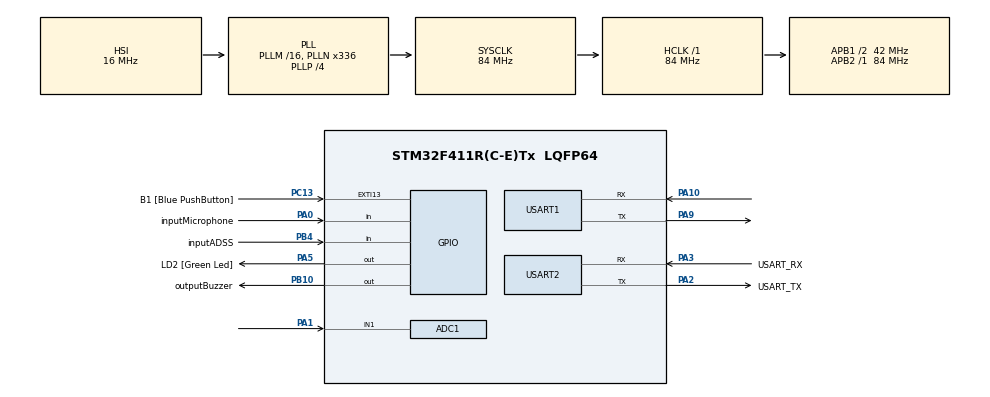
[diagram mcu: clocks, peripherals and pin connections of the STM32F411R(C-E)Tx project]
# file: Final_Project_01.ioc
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ADC1.Channel-0\#ChannelRegularConversion=ADC_CHANNEL_1
ADC1.NbrOfConversionFlag=1
ADC1.Rank-0\#ChannelRegularConversion=1
ADC1.SamplingTime-0\#ChannelRegularConversion=ADC_SAMPLETIME_3CYCLES
ADC1.master=1
Dma.Request0=USART2_RX
Dma.Request1=USART2_TX
Dma.Request2=USART1_RX
Dma.Request3=USART1_TX
Dma.USART1_RX.2.Direction=DMA_PERIPH_TO_MEMORY
Dma.USART1_RX.2.FIFOMode=DMA_FIFOMODE_DISABLE
Dma.USART1_RX.2.Instance=DMA2_Stream2
Dma.USART1_RX.2.MemDataAlignment=DMA_MDATAALIGN_BYTE
Dma.USART1_RX.2.MemInc=DMA_MINC_ENABLE
Dma.USART1_RX.2.Mode=DMA_NORMAL
Dma.USART1_RX.2.PeriphDataAlignment=DMA_PDATAALIGN_BYTE
Dma.USART1_RX.2.PeriphInc=DMA_PINC_DISABLE
Dma.USART1_RX.2.Priority=DMA_PRIORITY_LOW
Dma.USART1_TX.3.Direction=DMA_MEMORY_TO_PERIPH
Dma.USART1_TX.3.FIFOMode=DMA_FIFOMODE_DISABLE
Dma.USART1_TX.3.Instance=DMA2_Stream7
Dma.USART1_TX.3.MemDataAlignment=DMA_MDATAALIGN_BYTE
Dma.USART1_TX.3.MemInc=DMA_MINC_ENABLE
Dma.USART1_TX.3.Mode=DMA_NORMAL
Dma.USART1_TX.3.PeriphDataAlignment=DMA_PDATAALIGN_BYTE
Dma.USART1_TX.3.PeriphInc=DMA_PINC_DISABLE
Dma.USART1_TX.3.Priority=DMA_PRIORITY_LOW
Dma.USART2_RX.0.Direction=DMA_PERIPH_TO_MEMORY
Dma.USART2_RX.0.FIFOMode=DMA_FIFOMODE_DISABLE
Dma.USART2_RX.0.Instance=DMA1_Stream5
Dma.USART2_RX.0.MemDataAlignment=DMA_MDATAALIGN_BYTE
Dma.USART2_RX.0.MemInc=DMA_MINC_ENABLE
Dma.USART2_RX.0.Mode=DMA_NORMAL
Dma.USART2_RX.0.PeriphDataAlignment=DMA_PDATAALIGN_BYTE
Dma.USART2_RX.0.PeriphInc=DMA_PINC_DISABLE
Dma.USART2_RX.0.Priority=DMA_PRIORITY_LOW
Dma.USART2_TX.1.Direction=DMA_MEMORY_TO_PERIPH
Dma.USART2_TX.1.FIFOMode=DMA_FIFOMODE_DISABLE
Dma.USART2_TX.1.Instance=DMA1_Stream6
Dma.USART2_TX.1.MemDataAlignment=DMA_MDATAALIGN_BYTE
Dma.USART2_TX.1.MemInc=DMA_MINC_ENABLE
Dma.USART2_TX.1.Mode=DMA_NORMAL
Dma.USART2_TX.1.PeriphDataAlignment=DMA_PDATAALIGN_BYTE
Dma.USART2_TX.1.PeriphInc=DMA_PINC_DISABLE
Dma.USART2_TX.1.Priority=DMA_PRIORITY_LOW
Mcu.Family=STM32F4
Mcu.Name=STM32F411R(C-E)Tx
Mcu.Package=LQFP64
NVIC.DMA1_Stream5_IRQn=true\:0\:0\:false\:false\:true\:false\:true\:true
NVIC.DMA1_Stream6_IRQn=true\:0\:0\:false\:false\:true\:false\:true\:true
NVIC.DMA2_Stream2_IRQn=true\:0\:0\:false\:false\:true\:false\:true\:true
NVIC.DMA2_Stream7_IRQn=true\:0\:0\:false\:false\:true\:false\:true\:true
NVIC.EXTI15_10_IRQn=true\:0\:0\:false\:false\:true\:true\:true\:true
NVIC.PriorityGroup=NVIC_PRIORITYGROUP_0
NVIC.USART2_IRQn=true\:0\:0\:false\:false\:true\:true\:true\:true
PA0-WKUP.GPIO_Label=inputMicrophone
PA0-WKUP.Signal=GPIO_Input
PA1.Signal=ADCx_IN1
PA10.Mode=Asynchronous
PA10.Signal=USART1_RX
PA13.GPIO_Label=TMS
PA13.Mode=Serial_Wire
PA13.Signal=SYS_JTMS-SWDIO
PA14.GPIO_Label=TCK
PA14.Mode=Serial_Wire
PA14.Signal=SYS_JTCK-SWCLK
PA2.GPIO_Label=USART_TX
PA2.Mode=Asynchronous
PA2.Signal=USART2_TX
PA3.GPIO_Label=USART_RX
PA3.Mode=Asynchronous
PA3.Signal=USART2_RX
PA5.GPIO_Label=LD2 [Green Led]
PA5.Signal=GPIO_Output
PA9.Mode=Asynchronous
PA9.Signal=USART1_TX
PB10.GPIO_Label=outputBuzzer
PB10.Signal=GPIO_Output
PB3.GPIO_Label=SWO
PB3.Signal=SYS_JTDO-SWO
PB4.GPIO_Label=inputADSS
PB4.Signal=GPIO_Input
PC13-ANTI_TAMP.GPIO_Label=B1 [Blue PushButton]
PC13-ANTI_TAMP.GPIO_ModeDefaultEXTI=GPIO_MODE_IT_FALLING
PC13-ANTI_TAMP.Signal=GPXTI13
PC14-OSC32_IN.Mode=LSE-External-Oscillator
PC14-OSC32_IN.Signal=RCC_OSC32_IN
PC15-OSC32_OUT.Mode=LSE-External-Oscillator
PC15-OSC32_OUT.Signal=RCC_OSC32_OUT
PH0\ -\ OSC_IN.Mode=HSE-External-Clock-Source
PH0\ -\ OSC_IN.Signal=RCC_OSC_IN
PH1\ -\ OSC_OUT.Mode=HSE-External-Clock-Source
PH1\ -\ OSC_OUT.Signal=RCC_OSC_OUT
ProjectManager.HeapSize=0x200
ProjectManager.StackSize=0x400
ProjectManager.TargetToolchain=STM32CubeIDE
RCC.48MHZClocksFreq_Value=84000000
RCC.AHBFreq_Value=84000000
RCC.APB1CLKDivider=RCC_HCLK_DIV2
RCC.APB1Freq_Value=42000000
RCC.APB1TimFreq_Value=84000000
RCC.APB2Freq_Value=84000000
RCC.APB2TimFreq_Value=84000000
RCC.CortexFreq_Value=84000000
RCC.FLatency-AdvancedSettings=FLASH_LATENCY_2
RCC.HCLKFreq_Value=84000000
RCC.HSE_VALUE=8000000
RCC.HSI_VALUE=16000000
RCC.PLLN=336
RCC.PLLP=RCC_PLLP_DIV4
RCC.SYSCLKFreq_VALUE=84000000
RCC.SYSCLKSource=RCC_SYSCLKSOURCE_PLLCLK
RCC.VCOOutputFreq_Value=336000000
SH.ADCx_IN1.0=ADC1_IN1,IN1
USART1.VirtualMode=VM_ASYNC
USART2.VirtualMode=VM_ASYNC
board=NUCLEO-F411RE

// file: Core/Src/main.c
/* USER CODE BEGIN Header */
/**
 ******************************************************************************
 * @file           : main.c
 * @brief          : Main program body
 ******************************************************************************
 * @attention
 *
 * Copyright (c) 2025 STMicroelectronics.
 * All rights reserved.
 *
 * This software is licensed under terms that can be found in the LICENSE file
 * in the root directory of this software component.
 * If no LICENSE file comes with this software, it is provided AS-IS.
 *
 ******************************************************************************
 */
/* USER CODE END Header */
#include "main.h"

ADC_HandleTypeDef hadc1;

UART_HandleTypeDef huart1;
UART_HandleTypeDef huart2;

/* USER CODE BEGIN PV */
volatile uint32_t last_object_seen_time = 0;  // เวลาล่าสุดที่เจอวัตถุ (IR)
volatile uint32_t last_noise_seen_time = 0;  // เวลาล่าสุดที่เจอเสียง (จาก A0)
int previous_alarm_state = 0;
/* USER CODE END PV */

void SystemClock_Config(void);
static void MX_GPIO_Init(void);
static void MX_USART2_UART_Init(void);
static void MX_ADC1_Init(void);
static void MX_USART1_UART_Init(void);
/* USER CODE BEGIN PFP */
void SendAlarmStatus(const char *status);
/* USER CODE END PFP */

int main(void) {

	/* MCU Configuration--------------------------------------------------------*/

	/* Reset of all peripherals, Initializes the Flash interface and the Systick. */
	HAL_Init();

	/* Configure the system clock */
	SystemClock_Config();

	/* Initialize all configured peripherals */
	MX_GPIO_Init();
	MX_USART2_UART_Init();
	MX_ADC1_Init();
	MX_USART1_UART_Init();

	/* Infinite loop */
	while (1) {
		/* -------- 1) อ่านสถานะจาก IR Sensor (Infrared_Pin, Active Low) -------- */
		GPIO_PinState ir_state = HAL_GPIO_ReadPin(Infrared_GPIO_Port,
		Infrared_Pin);
		if (ir_state == GPIO_PIN_RESET) {
			last_object_seen_time = HAL_GetTick();
		}
		// ถ้า 200ms ล่าสุดยังเคยเจอวัตถุอยู่ -> is_obstacle = 1
		uint8_t is_obstacle = (HAL_GetTick() - last_object_seen_time) < 200;

		/* -------- 2) อ่านเสียงจาก A0 (ADC1_CH1 = PA1) -------- */
		uint32_t min_val = 4095;
		uint32_t max_val = 0;
		uint64_t sum_val = 0;
		const int N = 500;  // จำนวน sample ต่อรอบ

		for (int i = 0; i < N; i++) {
			HAL_ADC_Start(&hadc1);
			HAL_ADC_PollForConversion(&hadc1, HAL_MAX_DELAY);
			uint32_t v = HAL_ADC_GetValue(&hadc1);
			HAL_ADC_Stop(&hadc1);

			if (v < min_val)
				min_val = v;
			if (v > max_val)
				max_val = v;
			sum_val += v;
		}

		uint32_t avg_val = (uint32_t) (sum_val / N);
		uint32_t range_val = max_val - min_val;

		// ถ้า range ของสัญญาณเสียงเกิน threshold -> ถือว่าเจอเสียงดัง
		// (ค่า 1000 เป็นค่าลองเบื้องต้น ปรับเพิ่ม/ลดได้ตามของจริง)
		if (range_val > 1000) {
			last_noise_seen_time = HAL_GetTick();
		}

		// 2 วินาทีล่าสุดถ้ายังเจอเสียงดัง -> is_noise = 1
		uint8_t is_noise = (HAL_GetTick() - last_noise_seen_time) < 2000;

		/* -------- (Debug optional) แสดงค่าเสียงบางครั้ง -------- */
		static uint32_t last_print = 0;
		if (HAL_GetTick() - last_print > 100) {
			char buf[80];
			snprintf(buf, sizeof(buf),
					"Sound: range=%lu avg=%lu (thr=1000)\r\n",
					(unsigned long) range_val, (unsigned long) avg_val);
			HAL_UART_Transmit(&huart2, (uint8_t*) buf, strlen(buf), 50);
			last_print = HAL_GetTick();
		}

		/* -------- 3) รวมเป็นสถานะ Alarm -------- */
		uint8_t current_alarm_state = (is_obstacle || is_noise);

		/* -------- 4) ถ้าสถานะ Alarm เปลี่ยน -> รายงาน + คุม LED/Buzzer -------- */
		if (current_alarm_state != previous_alarm_state) {
			char msg[100];

			if (current_alarm_state == 1) {
				// Alarm ON
				sprintf(msg, "ALARM! State: %s%s\r\n",
						is_obstacle ? "OBSTACLE " : "",
						is_noise ? "NOISE" : "");

				// เปิด LED
				HAL_GPIO_WritePin(LED_GPIO_Port, LED_Pin, GPIO_PIN_SET);

				// ส่งสถานะไป ESP32
				if (is_obstacle && is_noise) {
					SendAlarmStatus("ALARM_BOTH\r\n");
				} else if (is_obstacle) {
					SendAlarmStatus("ALARM_OBSTACLE\r\n");
				} else if (is_noise) {
					SendAlarmStatus("ALARM_NOISE\r\n");
				}

			} else {
				// Alarm OFF
				sprintf(msg, "CLEARED! System Idle.\r\n");

				// ปิด LED
				HAL_GPIO_WritePin(LED_GPIO_Port, LED_Pin, GPIO_PIN_RESET);

				// ปิด Buzzer ทันที
				HAL_GPIO_WritePin(Buzzer_GPIO_Port, Buzzer_Pin, GPIO_PIN_RESET);

				// ส่งสถานะไป ESP32
				SendAlarmStatus("ALARM_CLEARED\r\n");
			}

			HAL_UART_Transmit(&huart2, (uint8_t*) msg, strlen(msg),
			HAL_MAX_DELAY);
			previous_alarm_state = current_alarm_state;
		}

		/* -------- 5) สร้างเสียง Buzzer ขณะ Alarm ON -------- */
		if (current_alarm_state == 1) {
			// Toggle Buzzer ให้เกิดโทนเสียง (ความถี่ประมาณ 500Hz ถ้าหน่วง 1ms)
			HAL_GPIO_TogglePin(Buzzer_GPIO_Port, Buzzer_Pin);
			HAL_Delay(1);
		} else {
			HAL_Delay(10); // Idle เบา ๆ ตอนไม่มี Alarm
		}
	}
}

void SystemClock_Config(void) {
	RCC_OscInitTypeDef RCC_OscInitStruct = { 0 };
	RCC_ClkInitTypeDef RCC_ClkInitStruct = { 0 };

	/** Configure the main internal regulator output voltage
	 */
	__HAL_RCC_PWR_CLK_ENABLE();
	__HAL_PWR_VOLTAGESCALING_CONFIG(PWR_REGULATOR_VOLTAGE_SCALE1);

	/** Initializes the RCC Oscillators according to the specified parameters
	 * in the RCC_OscInitTypeDef structure.
	 */
	RCC_OscInitStruct.OscillatorType = RCC_OSCILLATORTYPE_HSI;
	RCC_OscInitStruct.HSIState = RCC_HSI_ON;
	RCC_OscInitStruct.HSICalibrationValue = RCC_HSICALIBRATION_DEFAULT;
	RCC_OscInitStruct.PLL.PLLState = RCC_PLL_ON;
	RCC_OscInitStruct.PLL.PLLSource = RCC_PLLSOURCE_HSI;
	RCC_OscInitStruct.PLL.PLLM = 16;
	RCC_OscInitStruct.PLL.PLLN = 336;
	RCC_OscInitStruct.PLL.PLLP = RCC_PLLP_DIV4;
	RCC_OscInitStruct.PLL.PLLQ = 4;
	if (HAL_RCC_OscConfig(&RCC_OscInitStruct) != HAL_OK) {
		Error_Handler();
	}

	/** Initializes the CPU, AHB and APB buses clocks
	 */
	RCC_ClkInitStruct.ClockType = RCC_CLOCKTYPE_HCLK | RCC_CLOCKTYPE_SYSCLK
			| RCC_CLOCKTYPE_PCLK1 | RCC_CLOCKTYPE_PCLK2;
	RCC_ClkInitStruct.SYSCLKSource = RCC_SYSCLKSOURCE_PLLCLK;
	RCC_ClkInitStruct.AHBCLKDivider = RCC_SYSCLK_DIV1;
	RCC_ClkInitStruct.APB1CLKDivider = RCC_HCLK_DIV2;
	RCC_ClkInitStruct.APB2CLKDivider = RCC_HCLK_DIV1;

	if (HAL_RCC_ClockConfig(&RCC_ClkInitStruct, FLASH_LATENCY_2) != HAL_OK) {
		Error_Handler();
	}
}

static void MX_ADC1_Init(void) {

	ADC_ChannelConfTypeDef sConfig = { 0 };

	/** Configure the global features of the ADC (Clock, Resolution, Data Alignment and number of conversion)
	 */
	hadc1.Instance = ADC1;
	hadc1.Init.ClockPrescaler = ADC_CLOCK_SYNC_PCLK_DIV4;
	hadc1.Init.Resolution = ADC_RESOLUTION_12B;
	hadc1.Init.ScanConvMode = DISABLE;
	hadc1.Init.ContinuousConvMode = DISABLE;
	hadc1.Init.DiscontinuousConvMode = DISABLE;
	hadc1.Init.ExternalTrigConvEdge = ADC_EXTERNALTRIGCONVEDGE_NONE;
	hadc1.Init.ExternalTrigConv = ADC_SOFTWARE_START;
	hadc1.Init.DataAlign = ADC_DATAALIGN_RIGHT;
	hadc1.Init.NbrOfConversion = 1;
	hadc1.Init.DMAContinuousRequests = DISABLE;
	hadc1.Init.EOCSelection = ADC_EOC_SINGLE_CONV;
	if (HAL_ADC_Init(&hadc1) != HAL_OK) {
		Error_Handler();
	}

	/** Configure for the selected ADC regular channel its corresponding rank in the sequencer and its sample time.
	 */
	sConfig.Channel = ADC_CHANNEL_1;
	sConfig.Rank = 1;
	sConfig.SamplingTime = ADC_SAMPLETIME_3CYCLES;
	if (HAL_ADC_ConfigChannel(&hadc1, &sConfig) != HAL_OK) {
		Error_Handler();
	}

}

static void MX_USART1_UART_Init(void) {

	huart1.Instance = USART1;
	huart1.Init.BaudRate = 115200;
	huart1.Init.WordLength = UART_WORDLENGTH_8B;
	huart1.Init.StopBits = UART_STOPBITS_1;
	huart1.Init.Parity = UART_PARITY_NONE;
	huart1.Init.Mode = UART_MODE_TX_RX;
	huart1.Init.HwFlowCtl = UART_HWCONTROL_NONE;
	huart1.Init.OverSampling = UART_OVERSAMPLING_16;
	if (HAL_UART_Init(&huart1) != HAL_OK) {
		Error_Handler();
	}

}

static void MX_USART2_UART_Init(void) {

	huart2.Instance = USART2;
	huart2.Init.BaudRate = 115200;
	huart2.Init.WordLength = UART_WORDLENGTH_8B;
	huart2.Init.StopBits = UART_STOPBITS_1;
	huart2.Init.Parity = UART_PARITY_NONE;
	huart2.Init.Mode = UART_MODE_TX_RX;
	huart2.Init.HwFlowCtl = UART_HWCONTROL_NONE;
	huart2.Init.OverSampling = UART_OVERSAMPLING_16;
	if (HAL_UART_Init(&huart2) != HAL_OK) {
		Error_Handler();
	}

}

static void MX_GPIO_Init(void) {
	GPIO_InitTypeDef GPIO_InitStruct = { 0 };

	/* GPIO Ports Clock Enable */
	__HAL_RCC_GPIOC_CLK_ENABLE();
	__HAL_RCC_GPIOH_CLK_ENABLE();
	__HAL_RCC_GPIOA_CLK_ENABLE();
	__HAL_RCC_GPIOB_CLK_ENABLE();

	/*Configure GPIO pin Output Level */
	HAL_GPIO_WritePin(LED_GPIO_Port, LED_Pin, GPIO_PIN_RESET);

	/*Configure GPIO pin Output Level */
	HAL_GPIO_WritePin(Buzzer_GPIO_Port, Buzzer_Pin, GPIO_PIN_RESET);

	/*Configure GPIO pin : B1_Pin */
	GPIO_InitStruct.Pin = B1_Pin;
	GPIO_InitStruct.Mode = GPIO_MODE_IT_FALLING;
	GPIO_InitStruct.Pull = GPIO_NOPULL;
	HAL_GPIO_Init(B1_GPIO_Port, &GPIO_InitStruct);

	/*Configure GPIO pin : SOUND_IN_Pin */
	GPIO_InitStruct.Pin = SOUND_IN_Pin;
	GPIO_InitStruct.Mode = GPIO_MODE_INPUT;
	GPIO_InitStruct.Pull = GPIO_PULLDOWN;
	HAL_GPIO_Init(SOUND_IN_GPIO_Port, &GPIO_InitStruct);

	/*Configure GPIO pin : LED_Pin */
	GPIO_InitStruct.Pin = LED_Pin;
	GPIO_InitStruct.Mode = GPIO_MODE_OUTPUT_PP;
	GPIO_InitStruct.Pull = GPIO_NOPULL;
	GPIO_InitStruct.Speed = GPIO_SPEED_FREQ_LOW;
	HAL_GPIO_Init(LED_GPIO_Port, &GPIO_InitStruct);

	/*Configure GPIO pin : Buzzer_Pin */
	GPIO_InitStruct.Pin = Buzzer_Pin;
	GPIO_InitStruct.Mode = GPIO_MODE_OUTPUT_PP;
	GPIO_InitStruct.Pull = GPIO_NOPULL;
	GPIO_InitStruct.Speed = GPIO_SPEED_FREQ_LOW;
	HAL_GPIO_Init(Buzzer_GPIO_Port, &GPIO_InitStruct);

	/*Configure GPIO pin : Infrared_Pin */
	GPIO_InitStruct.Pin = Infrared_Pin;
	GPIO_InitStruct.Mode = GPIO_MODE_INPUT;
	GPIO_InitStruct.Pull = GPIO_NOPULL;
	HAL_GPIO_Init(Infrared_GPIO_Port, &GPIO_InitStruct);

}

/* USER CODE BEGIN 4 */
void SendAlarmStatus(const char *status) {
	HAL_UART_Transmit(&huart1, (uint8_t*) status, strlen(status), 10);
}
/* USER CODE END 4 */

void Error_Handler(void) {
	__disable_irq();
	while (1) {
	}
}
